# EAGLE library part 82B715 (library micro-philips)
I2C bus extender

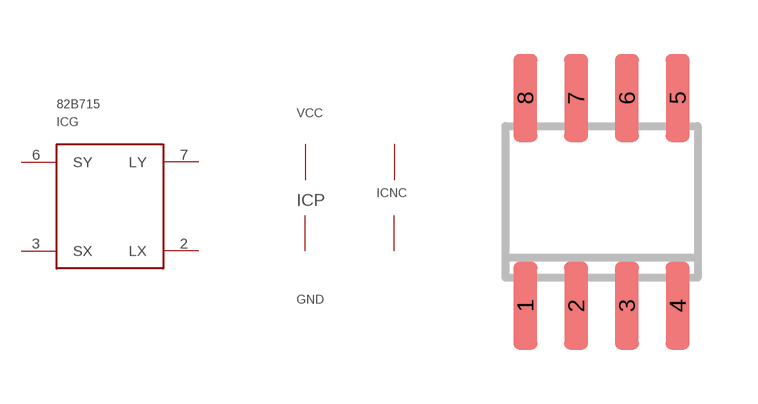
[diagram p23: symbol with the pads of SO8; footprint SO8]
Designator prefix IC; gates G=82B715 P=PWR2 NC=NC2

## 82B715TD  [SO8]
1  NC:NC  nc
2  G:LX
3  G:SX
4  P:GND  pwr
5  NC:NC  nc
6  G:SY
7  G:LY
8  P:VCC  pwr

## Footprint SO8 (pad centres in mm)
Small Outline Package
smd 0.6 x 2.2: 1 -1.905,-2.6; 2 -0.635,-2.6; 3 0.635,-2.6; 4 1.905,-2.6; 5 1.905,2.6; 6 0.635,2.6; 7 -0.635,2.6; 8 -1.905,2.6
